VERSION 5.7 ;
  NOWIREEXTENSIONATPIN ON ;
  DIVIDERCHAR "/" ;
  BUSBITCHARS "[]" ;
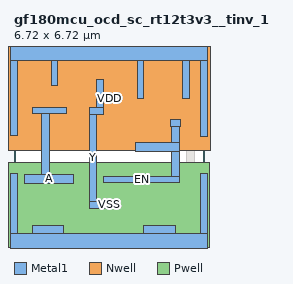
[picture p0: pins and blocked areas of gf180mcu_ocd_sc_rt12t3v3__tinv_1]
MACRO gf180mcu_ocd_sc_rt12t3v3__tinv_1
  CLASS CORE ;
  FOREIGN gf180mcu_ocd_sc_rt12t3v3__tinv_1 ;
  ORIGIN 0.000 0.000 ;
  SIZE 6.720 BY 6.720 ;
  SYMMETRY X Y ;
  SITE unithd ;
  PIN A
    DIRECTION INPUT ;
    USE SIGNAL ;
    ANTENNAGATEAREA 1.672300 ;
    PORT
      LAYER Metal1 ;
        RECT 0.670 4.540 1.870 4.770 ;
        RECT 0.990 2.405 1.240 4.540 ;
        RECT 0.360 2.075 2.120 2.405 ;
    END
  END A
  PIN EN
    DIRECTION INPUT ;
    USE SIGNAL ;
    ANTENNAGATEAREA 2.625000 ;
    PORT
      LAYER Metal1 ;
        RECT 5.525 4.090 5.875 4.320 ;
        RECT 5.580 3.525 5.840 4.090 ;
        RECT 4.290 3.195 5.840 3.525 ;
        RECT 5.580 2.325 5.840 3.195 ;
        RECT 3.180 2.095 5.870 2.325 ;
    END
  END EN
  PIN Y
    DIRECTION OUTPUT ;
    USE SIGNAL ;
    ANTENNADIFFAREA 0.976900 ;
    PORT
      LAYER Metal1 ;
        RECT 2.910 4.770 3.170 5.730 ;
        RECT 2.670 4.525 3.170 4.770 ;
        RECT 2.670 1.425 2.930 4.525 ;
        RECT 2.670 1.195 3.340 1.425 ;
    END
  END Y
  PIN VDD
    DIRECTION INOUT ;
    USE POWER ;
    SHAPE ABUTMENT ;
    PORT
      LAYER Nwell ;
        RECT -0.660 3.245 7.280 7.330 ;
      LAYER Metal1 ;
        RECT -0.115 6.420 6.835 7.020 ;
        RECT -0.115 3.750 0.115 6.420 ;
        RECT 1.325 5.520 1.555 6.420 ;
        RECT 4.365 5.065 4.595 6.420 ;
        RECT 5.965 5.060 6.195 6.420 ;
        RECT 6.605 3.745 6.835 6.420 ;
    END
  END VDD
  PIN VSS
    DIRECTION INOUT ;
    USE GROUND ;
    SHAPE ABUTMENT ;
    PORT
      LAYER Pwell ;
        RECT -0.180 -0.180 6.900 2.815 ;
      LAYER Metal1 ;
        RECT -0.115 0.300 0.115 2.410 ;
        RECT 0.640 0.300 1.750 0.585 ;
        RECT 4.590 0.300 5.700 0.585 ;
        RECT 6.605 0.300 6.835 2.410 ;
        RECT -0.115 -0.300 6.835 0.300 ;
    END
  END VSS
  OBS
      LAYER Metal1 ;
        RECT 0.525 5.290 0.755 6.190 ;
        RECT 2.125 5.960 3.955 6.190 ;
        RECT 2.125 5.290 2.355 5.960 ;
        RECT 0.525 5.060 2.355 5.290 ;
        RECT 3.725 5.055 3.955 5.960 ;
        RECT 5.165 4.820 5.395 6.180 ;
        RECT 4.340 4.770 6.375 4.820 ;
        RECT 3.405 4.560 6.375 4.770 ;
        RECT 3.405 4.540 4.620 4.560 ;
        RECT 2.190 1.425 2.420 1.815 ;
        RECT 6.115 1.425 6.375 4.560 ;
        RECT 1.020 1.195 2.420 1.425 ;
        RECT 4.945 1.195 6.375 1.425 ;
        RECT 2.190 0.770 2.420 1.195 ;
  END
END gf180mcu_ocd_sc_rt12t3v3__tinv_1
END LIBRARY

